One B-rep face of a CAD part: STEP entity #5036.
In plain terms, the planar face has unit normal (-1, 0, 0).
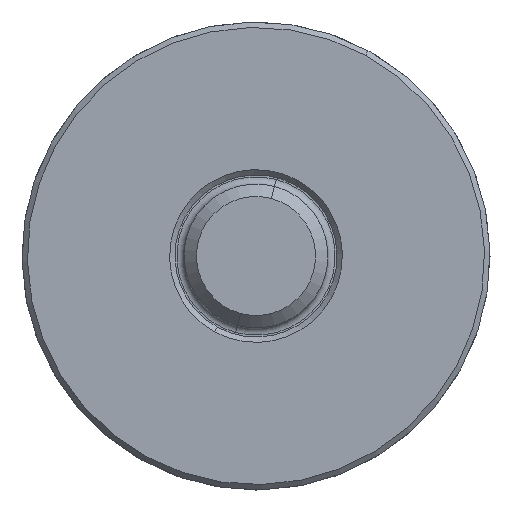
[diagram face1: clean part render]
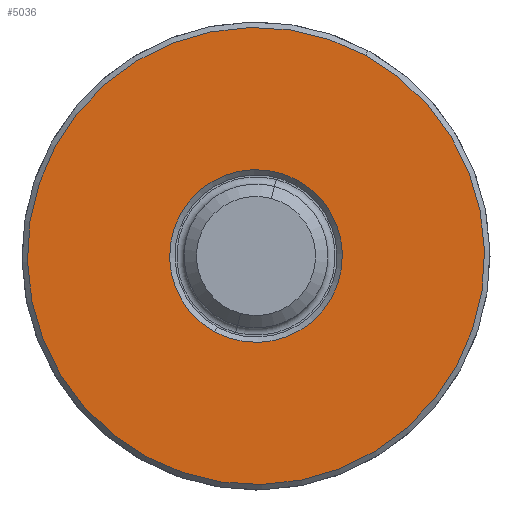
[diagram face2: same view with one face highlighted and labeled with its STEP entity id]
Its self-contained STEP definition (entity closure, numbers rounded to 3 decimals):
#295 = CARTESIAN_POINT ( 'NONE',  ( 0., 0., -4.8 ) ) ;
#549 = DIRECTION ( 'NONE',  ( 0., 0., 1. ) ) ;
#1185 = CARTESIAN_POINT ( 'NONE',  ( 0., 0., 0. ) ) ;
#1352 = EDGE_CURVE ( 'NONE', #10054, #8884, #5820, .T. ) ;
#1468 = ORIENTED_EDGE ( 'NONE', *, *, #6591, .T. ) ;
#1520 = AXIS2_PLACEMENT_3D ( 'NONE', #6528, #5650, #6492 ) ;
#1705 = CARTESIAN_POINT ( 'NONE',  ( 0., 0., -12.7 ) ) ;
#2369 = AXIS2_PLACEMENT_3D ( 'NONE', #1185, #2823, #10140 ) ;
#2610 = FACE_OUTER_BOUND ( 'NONE', #6779, .T. ) ;
#2734 = ORIENTED_EDGE ( 'NONE', *, *, #1352, .T. ) ;
#2823 = DIRECTION ( 'NONE',  ( -1., 0., 0. ) ) ;
#2915 = VERTEX_POINT ( 'NONE', #7607 ) ;
#3119 = AXIS2_PLACEMENT_3D ( 'NONE', #9881, #9737, #4891 ) ;
#3484 = EDGE_CURVE ( 'NONE', #2915, #3830, #5076, .T. ) ;
#3830 = VERTEX_POINT ( 'NONE', #1705 ) ;
#4350 = DIRECTION ( 'NONE',  ( 0., 0., 1. ) ) ;
#4486 = ORIENTED_EDGE ( 'NONE', *, *, #3484, .T. ) ;
#4614 = CARTESIAN_POINT ( 'NONE',  ( 0., 0., 0. ) ) ;
#4891 = DIRECTION ( 'NONE',  ( 0., 0., 1. ) ) ;
#5036 = ADVANCED_FACE ( 'NONE', ( #9499, #2610 ), #5694, .T. ) ;
#5076 = CIRCLE ( 'NONE', #9264, 12.7 ) ;
#5650 = DIRECTION ( 'NONE',  ( -1., 0., 0. ) ) ;
#5694 = PLANE ( 'NONE',  #1520 ) ;
#5773 = EDGE_LOOP ( 'NONE', ( #2734, #8330 ) ) ;
#5820 = CIRCLE ( 'NONE', #3119, 4.8 ) ;
#6492 = DIRECTION ( 'NONE',  ( 0., 0., 1. ) ) ;
#6528 = CARTESIAN_POINT ( 'NONE',  ( 0., 0., 0. ) ) ;
#6591 = EDGE_CURVE ( 'NONE', #3830, #2915, #6701, .T. ) ;
#6701 = CIRCLE ( 'NONE', #2369, 12.7 ) ;
#6779 = EDGE_LOOP ( 'NONE', ( #1468, #4486 ) ) ;
#7233 = AXIS2_PLACEMENT_3D ( 'NONE', #4614, #8716, #549 ) ;
#7509 = CIRCLE ( 'NONE', #7233, 4.8 ) ;
#7607 = CARTESIAN_POINT ( 'NONE',  ( 0., 0., 12.7 ) ) ;
#8330 = ORIENTED_EDGE ( 'NONE', *, *, #10165, .T. ) ;
#8392 = CARTESIAN_POINT ( 'NONE',  ( 0., 0., 0. ) ) ;
#8716 = DIRECTION ( 'NONE',  ( 1., 0., 0. ) ) ;
#8884 = VERTEX_POINT ( 'NONE', #295 ) ;
#9222 = DIRECTION ( 'NONE',  ( -1., 0., 0. ) ) ;
#9264 = AXIS2_PLACEMENT_3D ( 'NONE', #8392, #9222, #4350 ) ;
#9370 = CARTESIAN_POINT ( 'NONE',  ( 0., 0., 4.8 ) ) ;
#9499 = FACE_BOUND ( 'NONE', #5773, .T. ) ;
#9737 = DIRECTION ( 'NONE',  ( 1., 0., 0. ) ) ;
#9881 = CARTESIAN_POINT ( 'NONE',  ( 0., 0., 0. ) ) ;
#10054 = VERTEX_POINT ( 'NONE', #9370 ) ;
#10140 = DIRECTION ( 'NONE',  ( 0., 0., 1. ) ) ;
#10165 = EDGE_CURVE ( 'NONE', #8884, #10054, #7509, .T. ) ;
